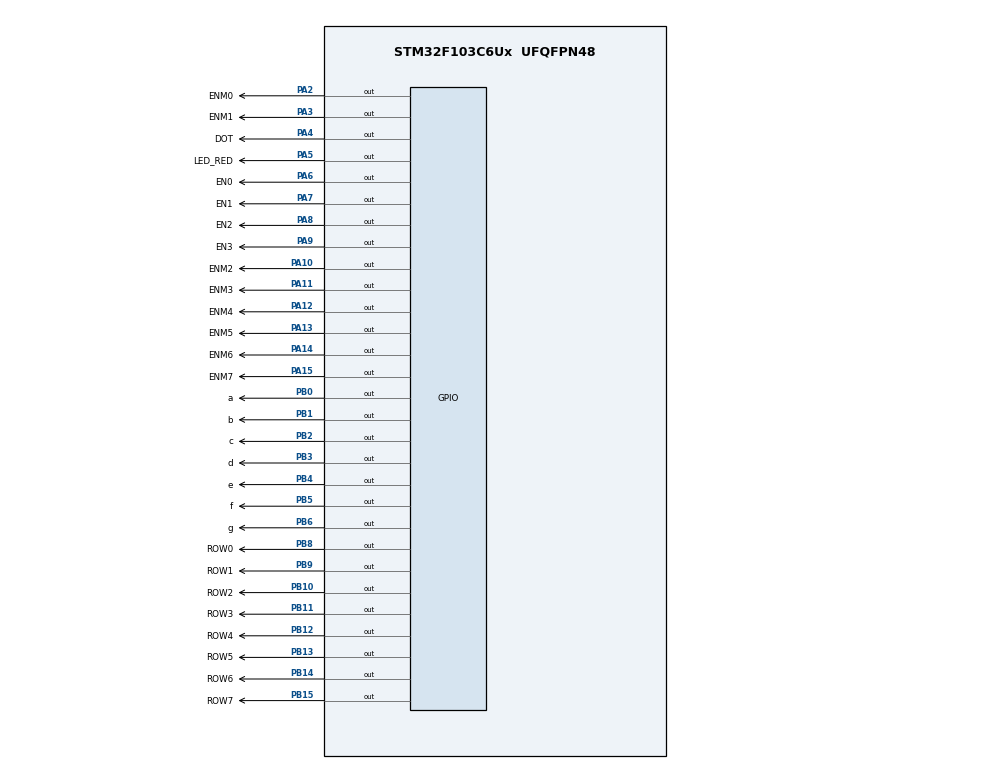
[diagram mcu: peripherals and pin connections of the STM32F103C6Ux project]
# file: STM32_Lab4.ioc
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Mcu.Family=STM32F1
Mcu.Name=STM32F103C6Ux
Mcu.Package=UFQFPN48
NVIC.PriorityGroup=NVIC_PRIORITYGROUP_4
NVIC.TIM2_IRQn=true\:0\:0\:false\:false\:true\:true\:true
PA10.GPIO_Label=ENM2
PA10.PinState=GPIO_PIN_RESET
PA10.Signal=GPIO_Output
PA11.GPIO_Label=ENM3
PA11.PinState=GPIO_PIN_RESET
PA11.Signal=GPIO_Output
PA12.GPIO_Label=ENM4
PA12.PinState=GPIO_PIN_RESET
PA12.Signal=GPIO_Output
PA13.GPIO_Label=ENM5
PA13.PinState=GPIO_PIN_RESET
PA13.Signal=GPIO_Output
PA14.GPIO_Label=ENM6
PA14.PinState=GPIO_PIN_RESET
PA14.Signal=GPIO_Output
PA15.GPIO_Label=ENM7
PA15.PinState=GPIO_PIN_RESET
PA15.Signal=GPIO_Output
PA2.GPIO_Label=ENM0
PA2.PinState=GPIO_PIN_RESET
PA2.Signal=GPIO_Output
PA3.GPIO_Label=ENM1
PA3.PinState=GPIO_PIN_RESET
PA3.Signal=GPIO_Output
PA4.GPIO_Label=DOT
PA4.PinState=GPIO_PIN_SET
PA4.Signal=GPIO_Output
PA5.GPIO_Label=LED_RED
PA5.PinState=GPIO_PIN_SET
PA5.Signal=GPIO_Output
PA6.GPIO_Label=EN0
PA6.PinState=GPIO_PIN_SET
PA6.Signal=GPIO_Output
PA7.GPIO_Label=EN1
PA7.PinState=GPIO_PIN_SET
PA7.Signal=GPIO_Output
PA8.GPIO_Label=EN2
PA8.PinState=GPIO_PIN_SET
PA8.Signal=GPIO_Output
PA9.GPIO_Label=EN3
PA9.PinState=GPIO_PIN_SET
PA9.Signal=GPIO_Output
PB0.GPIO_Label=a
PB0.PinState=GPIO_PIN_SET
PB0.Signal=GPIO_Output
PB1.GPIO_Label=b
PB1.PinState=GPIO_PIN_SET
PB1.Signal=GPIO_Output
PB10.GPIO_Label=ROW2
PB10.PinState=GPIO_PIN_RESET
PB10.Signal=GPIO_Output
PB11.GPIO_Label=ROW3
PB11.PinState=GPIO_PIN_RESET
PB11.Signal=GPIO_Output
PB12.GPIO_Label=ROW4
PB12.PinState=GPIO_PIN_RESET
PB12.Signal=GPIO_Output
PB13.GPIO_Label=ROW5
PB13.PinState=GPIO_PIN_RESET
PB13.Signal=GPIO_Output
PB14.GPIO_Label=ROW6
PB14.PinState=GPIO_PIN_RESET
PB14.Signal=GPIO_Output
PB15.GPIO_Label=ROW7
PB15.PinState=GPIO_PIN_RESET
PB15.Signal=GPIO_Output
PB2.GPIO_Label=c
PB2.PinState=GPIO_PIN_SET
PB2.Signal=GPIO_Output
PB3.GPIO_Label=d
PB3.PinState=GPIO_PIN_SET
PB3.Signal=GPIO_Output
PB4.GPIO_Label=e
PB4.PinState=GPIO_PIN_SET
PB4.Signal=GPIO_Output
PB5.GPIO_Label=f
PB5.PinState=GPIO_PIN_SET
PB5.Signal=GPIO_Output
PB6.GPIO_Label=g
PB6.PinState=GPIO_PIN_SET
PB6.Signal=GPIO_Output
PB8.GPIO_Label=ROW0
PB8.PinState=GPIO_PIN_RESET
PB8.Signal=GPIO_Output
PB9.GPIO_Label=ROW1
PB9.PinState=GPIO_PIN_RESET
PB9.Signal=GPIO_Output
ProjectManager.HeapSize=0x200
ProjectManager.StackSize=0x400
ProjectManager.TargetToolchain=STM32CubeIDE
RCC.APB1Freq_Value=8000000
RCC.APB2Freq_Value=8000000
TIM2.Period=9
TIM2.Prescaler=7999
VP_SYS_VS_ND.Mode=No_Debug
VP_TIM2_VS_ClockSourceINT.Mode=Internal
board=custom

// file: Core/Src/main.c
/* USER CODE BEGIN Header */
/**
  ******************************************************************************
  * @file           : main.c
  * @brief          : Lab 4 - Cooperative Scheduler (Bộ lập lịch hợp tác)
  ******************************************************************************
  * @attention
  *
  * <h2><center>&copy; Copyright (c) 2026 STMicroelectronics.
  * All rights reserved.</center></h2>
  *
  ******************************************************************************
  */
/* USER CODE END Header */
#include "main.h"

/* USER CODE BEGIN Includes */
#include "scheduler.h"
/* USER CODE END Includes */

TIM_HandleTypeDef htim2;

void SystemClock_Config(void);
static void MX_GPIO_Init(void);
static void MX_TIM2_Init(void);

/* USER CODE BEGIN 0 */

/* 5 tác vụ định kỳ điều khiển 5 đèn LED độc lập */
void Task_LED1_500ms(void) {
    HAL_GPIO_TogglePin(LED1_GPIO_Port, LED1_Pin);
}

void Task_LED2_1000ms(void) {
    HAL_GPIO_TogglePin(LED2_GPIO_Port, LED2_Pin);
}

void Task_LED3_1500ms(void) {
    HAL_GPIO_TogglePin(LED3_GPIO_Port, LED3_Pin);
}

void Task_LED4_2000ms(void) {
    HAL_GPIO_TogglePin(LED4_GPIO_Port, LED4_Pin);
}

void Task_LED5_2500ms(void) {
    HAL_GPIO_TogglePin(LED5_GPIO_Port, LED5_Pin);
}

/* USER CODE END 0 */

int main(void)
{

  /* MCU Configuration--------------------------------------------------------*/

  /* Reset of all peripherals, Initializes the Flash interface and the Systick. */
  HAL_Init();

  /* Configure the system clock */
  SystemClock_Config();

  /* Initialize all configured peripherals */
  MX_GPIO_Init();
  MX_TIM2_Init();
  /* USER CODE BEGIN 2 */

  /* 1. Khởi tạo bộ lập lịch trước khi bật ngắt Timer */
  SCH_Init();

  /* 2. Đăng ký 5 tác vụ định kỳ (1 tick = 10ms) */
  SCH_Add_Task(Task_LED1_500ms,  0, 50);   /* Chu kỳ 0.5s = 50 ticks  */
  SCH_Add_Task(Task_LED2_1000ms, 0, 100);  /* Chu kỳ 1.0s = 100 ticks */
  SCH_Add_Task(Task_LED3_1500ms, 0, 150);  /* Chu kỳ 1.5s = 150 ticks */
  SCH_Add_Task(Task_LED4_2000ms, 0, 200);  /* Chu kỳ 2.0s = 200 ticks */
  SCH_Add_Task(Task_LED5_2500ms, 0, 250);  /* Chu kỳ 2.5s = 250 ticks */

  /* 3. Bắt đầu Timer 2 sinh ngắt định kỳ mỗi 10ms */
  HAL_TIM_Base_Start_IT(&htim2);

  /* USER CODE END 2 */

  /* Infinite loop */
  /* USER CODE BEGIN WHILE */
  while (1)
  {
      /* Bộ điều phối kiểm tra và thực thi các tác vụ đã đến hạn */
      SCH_Dispatch_Tasks();
    /* USER CODE END WHILE */

  }
}

void SystemClock_Config(void)
{
  RCC_OscInitTypeDef RCC_OscInitStruct = {0};
  RCC_ClkInitTypeDef RCC_ClkInitStruct = {0};

  /** Initializes the RCC Oscillators according to the specified parameters
  * in the RCC_OscInitTypeDef structure.
  */
  RCC_OscInitStruct.OscillatorType = RCC_OSCILLATORTYPE_HSI;
  RCC_OscInitStruct.HSIState = RCC_HSI_ON;
  RCC_OscInitStruct.HSICalibrationValue = RCC_HSICALIBRATION_DEFAULT;
  RCC_OscInitStruct.PLL.PLLState = RCC_PLL_NONE;
  if (HAL_RCC_OscConfig(&RCC_OscInitStruct) != HAL_OK)
  {
    Error_Handler();
  }
  /** Initializes the CPU, AHB and APB buses clocks
  */
  RCC_ClkInitStruct.ClockType = RCC_CLOCKTYPE_HCLK|RCC_CLOCKTYPE_SYSCLK
                              |RCC_CLOCKTYPE_PCLK1|RCC_CLOCKTYPE_PCLK2;
  RCC_ClkInitStruct.SYSCLKSource = RCC_SYSCLKSOURCE_HSI;
  RCC_ClkInitStruct.AHBCLKDivider = RCC_SYSCLK_DIV1;
  RCC_ClkInitStruct.APB1CLKDivider = RCC_HCLK_DIV1;
  RCC_ClkInitStruct.APB2CLKDivider = RCC_HCLK_DIV1;

  if (HAL_RCC_ClockConfig(&RCC_ClkInitStruct, FLASH_LATENCY_0) != HAL_OK)
  {
    Error_Handler();
  }
}

static void MX_TIM2_Init(void)
{

  TIM_ClockConfigTypeDef sClockSourceConfig = {0};
  TIM_MasterConfigTypeDef sMasterConfig = {0};

  htim2.Instance = TIM2;
  htim2.Init.Prescaler = 7999;
  htim2.Init.CounterMode = TIM_COUNTERMODE_UP;
  htim2.Init.Period = 9;
  htim2.Init.ClockDivision = TIM_CLOCKDIVISION_DIV1;
  htim2.Init.AutoReloadPreload = TIM_AUTORELOAD_PRELOAD_DISABLE;
  if (HAL_TIM_Base_Init(&htim2) != HAL_OK)
  {
    Error_Handler();
  }
  sClockSourceConfig.ClockSource = TIM_CLOCKSOURCE_INTERNAL;
  if (HAL_TIM_ConfigClockSource(&htim2, &sClockSourceConfig) != HAL_OK)
  {
    Error_Handler();
  }
  sMasterConfig.MasterOutputTrigger = TIM_TRGO_RESET;
  sMasterConfig.MasterSlaveMode = TIM_MASTERSLAVEMODE_DISABLE;
  if (HAL_TIMEx_MasterConfigSynchronization(&htim2, &sMasterConfig) != HAL_OK)
  {
    Error_Handler();
  }

}

static void MX_GPIO_Init(void)
{
  GPIO_InitTypeDef GPIO_InitStruct = {0};

  /* GPIO Ports Clock Enable */
  __HAL_RCC_GPIOA_CLK_ENABLE();

  /* Tắt toàn bộ LED ban đầu (LED mắc tích cực mức thấp: SET = Tắt, RESET = Sáng) */
  HAL_GPIO_WritePin(GPIOA, LED1_Pin | LED2_Pin | LED3_Pin | LED4_Pin | LED5_Pin, GPIO_PIN_SET);

  /* Cấu hình các chân PA4 -> PA15 làm ngõ ra Push-Pull */
  GPIO_InitStruct.Pin = LED1_Pin | LED2_Pin | LED3_Pin | LED4_Pin | LED5_Pin ;
  GPIO_InitStruct.Mode = GPIO_MODE_OUTPUT_PP;
  GPIO_InitStruct.Pull = GPIO_NOPULL;
  GPIO_InitStruct.Speed = GPIO_SPEED_FREQ_LOW;
  HAL_GPIO_Init(GPIOA, &GPIO_InitStruct);
}

/* USER CODE BEGIN 4 */

/* Callback ngắt Timer 2 (gọi mỗi 10ms) */
void HAL_TIM_PeriodElapsedCallback(TIM_HandleTypeDef *htim)
{
  if (htim->Instance == TIM2) {
      SCH_Update();
  }
}

/* USER CODE END 4 */

void Error_Handler(void)
{
  __disable_irq();
  while (1)
  {
  }
}

/************************ (C) COPYRIGHT STMicroelectronics *****END OF FILE****/
